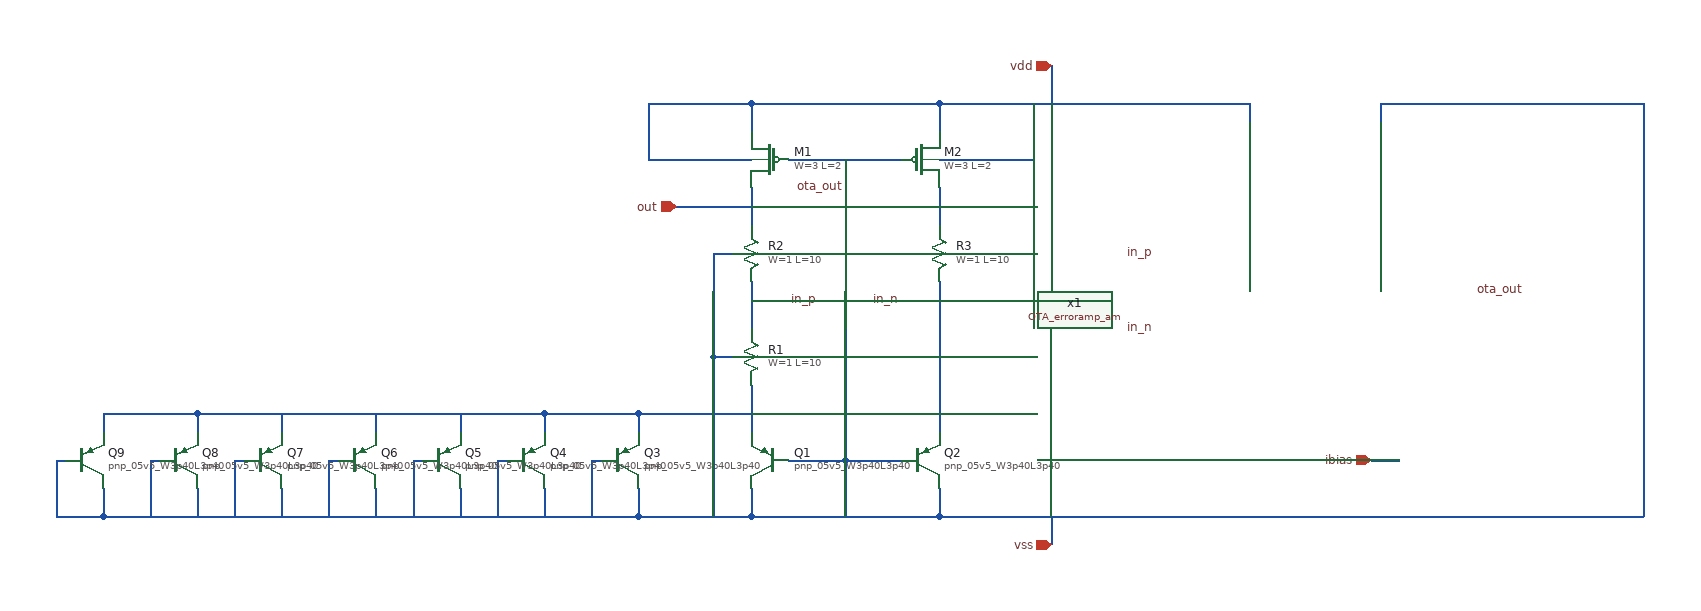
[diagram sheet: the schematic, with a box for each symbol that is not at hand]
v {xschem version=3.4.2 file_version=1.2
}
G {}
K {}
V {}
S {}
E {}
N 760 -70 760 -40 {
lab=vss}
N 960 -70 960 -40 {
lab=vss}
N 760 -180 760 -130 {
lab=#net1}
N 640 -150 640 -130 {
lab=#net1}
N 640 -150 760 -150 {
lab=#net1}
N 640 -70 640 -40 {
lab=vss}
N 640 -40 760 -40 {
lab=vss}
N 540 -150 540 -130 {
lab=#net1}
N 540 -150 640 -150 {
lab=#net1}
N 170 -150 170 -130 {
lab=#net1}
N 170 -150 540 -150 {
lab=#net1}
N 450 -150 450 -130 {
lab=#net1}
N 360 -150 360 -130 {
lab=#net1}
N 260 -150 260 -130 {
lab=#net1}
N 70 -150 70 -130 {
lab=#net1}
N 70 -150 170 -150 {
lab=#net1}
N 70 -70 70 -40 {
lab=vss}
N 70 -40 640 -40 {
lab=vss}
N 540 -70 540 -40 {
lab=vss}
N 450 -70 450 -40 {
lab=vss}
N 360 -70 360 -40 {
lab=vss}
N 260 -70 260 -40 {
lab=vss}
N 170 -70 170 -40 {
lab=vss}
N 590 -100 600 -100 {
lab=vss}
N 590 -100 590 -40 {
lab=vss}
N 490 -100 500 -100 {
lab=vss}
N 490 -100 490 -40 {
lab=vss}
N 400 -100 410 -100 {
lab=vss}
N 400 -100 400 -40 {
lab=vss}
N 310 -100 320 -100 {
lab=vss}
N 310 -100 310 -40 {
lab=vss}
N 210 -100 220 -100 {
lab=vss}
N 210 -100 210 -40 {
lab=vss}
N 120 -100 130 -100 {
lab=vss}
N 120 -100 120 -40 {
lab=vss}
N 20 -100 30 -100 {
lab=vss}
N 20 -100 20 -40 {
lab=vss}
N 20 -40 70 -40 {
lab=vss}
N 760 -290 760 -240 {
lab=in_p}
N 960 -290 960 -130 {
lab=in_n}
N 760 -40 960 -40 {
lab=vss}
N 760 -390 760 -350 {
lab=out}
N 960 -390 960 -360 {
lab=#net2}
N 960 -360 960 -350 {
lab=#net2}
N 800 -420 920 -420 {
lab=ota_out}
N 760 -480 760 -450 {
lab=vdd}
N 760 -480 960 -480 {
lab=vdd}
N 960 -480 960 -450 {
lab=vdd}
N 760 -270 800 -270 {
lab=in_p}
N 920 -270 960 -270 {
lab=in_n}
N 860 -420 860 -390 {
lab=ota_out}
N 960 -480 1290 -480 {
lab=vdd}
N 1290 -480 1290 -460 {
lab=vdd}
N 1430 -480 1430 -460 {
lab=vss}
N 1430 -480 1710 -480 {
lab=vss}
N 1710 -480 1710 -40 {
lab=vss}
N 960 -40 1710 -40 {
lab=vss}
N 1420 -100 1450 -100 {
lab=ibias}
N 1080 -520 1080 -480 {
lab=vdd}
N 1080 -40 1080 -10 {
lab=vss}
N 680 -370 760 -370 {
lab=out}
N 720 -320 740 -320 {
lab=vss}
N 720 -320 720 -210 {
lab=vss}
N 720 -210 740 -210 {
lab=vss}
N 720 -210 720 -40 {
lab=vss}
N 930 -320 940 -320 {
lab=vss}
N 860 -320 930 -320 {
lab=vss}
N 860 -320 860 -100 {
lab=vss}
N 800 -100 860 -100 {
lab=vss}
N 860 -100 920 -100 {
lab=vss}
N 860 -100 860 -40 {
lab=vss}
N 650 -420 760 -420 {
lab=vdd}
N 650 -480 650 -420 {
lab=vdd}
N 650 -480 760 -480 {
lab=vdd}
N 960 -420 1060 -420 {
lab=vdd}
N 1060 -480 1060 -420 {
lab=vdd}
C {sky130_fd_pr/pnp_05v5.sym} 780 -100 0 1 {name=Q1
model=pnp_05v5_W3p40L3p40
m=1
spiceprefix=X
}
C {sky130_fd_pr/pnp_05v5.sym} 940 -100 0 0 {name=Q2
model=pnp_05v5_W3p40L3p40
m=1
spiceprefix=X
}
C {sky130_fd_pr/pnp_05v5.sym} 620 -100 0 0 {name=Q3
model=pnp_05v5_W3p40L3p40
m=1
spiceprefix=X
}
C {sky130_fd_pr/pnp_05v5.sym} 520 -100 0 0 {name=Q4
model=pnp_05v5_W3p40L3p40
m=1
spiceprefix=X
}
C {sky130_fd_pr/pnp_05v5.sym} 430 -100 0 0 {name=Q5
model=pnp_05v5_W3p40L3p40
m=1
spiceprefix=X
}
C {sky130_fd_pr/pnp_05v5.sym} 340 -100 0 0 {name=Q6
model=pnp_05v5_W3p40L3p40
m=1
spiceprefix=X
}
C {sky130_fd_pr/pnp_05v5.sym} 240 -100 0 0 {name=Q7
model=pnp_05v5_W3p40L3p40
m=1
spiceprefix=X
}
C {sky130_fd_pr/pnp_05v5.sym} 150 -100 0 0 {name=Q8
model=pnp_05v5_W3p40L3p40
m=1
spiceprefix=X
}
C {sky130_fd_pr/pnp_05v5.sym} 50 -100 0 0 {name=Q9
model=pnp_05v5_W3p40L3p40
m=1
spiceprefix=X
}
C {sky130_fd_pr/res_xhigh_po.sym} 760 -210 0 0 {name=R1
W=1
L=10
model=res_xhigh_po
spiceprefix=X
mult=9}
C {sky130_fd_pr/res_xhigh_po.sym} 760 -320 0 0 {name=R2
W=1
L=10
model=res_xhigh_po
spiceprefix=X
mult=1}
C {sky130_fd_pr/res_xhigh_po.sym} 960 -320 0 0 {name=R3
W=1
L=10
model=res_xhigh_po
spiceprefix=X
mult=1}
C {devices/lab_pin.sym} 860 -390 0 0 {name=p1 sig_type=std_logic lab=ota_out}
C {devices/lab_pin.sym} 800 -270 2 0 {name=p2 sig_type=std_logic lab=in_p}
C {devices/lab_pin.sym} 920 -270 0 0 {name=p3 sig_type=std_logic lab=in_n}
C {devices/lab_pin.sym} 1190 -320 0 0 {name=p4 sig_type=std_logic lab=in_p}
C {devices/lab_pin.sym} 1190 -240 0 0 {name=p5 sig_type=std_logic lab=in_n}
C {devices/iopin.sym} 1080 -520 0 0 {name=p6 lab=vdd}
C {devices/iopin.sym} 1080 -10 0 0 {name=p7 lab=vss}
C {devices/lab_pin.sym} 1530 -280 2 0 {name=p8 sig_type=std_logic lab=ota_out}
C {devices/iopin.sym} 680 -370 2 0 {name=p9 lab=out}
C {devices/iopin.sym} 1420 -100 2 0 {name=p10 lab=ibias}
C {sky130_fd_pr/pfet_g5v0d10v5.sym} 780 -420 0 1 {name=M1
L=2
W=3
nf=1
mult=8
ad="'int((nf+1)/2) * W/nf * 0.29'" 
pd="'2*int((nf+1)/2) * (W/nf + 0.29)'"
as="'int((nf+2)/2) * W/nf * 0.29'" 
ps="'2*int((nf+2)/2) * (W/nf + 0.29)'"
nrd="'0.29 / W'" nrs="'0.29 / W'"
sa=0 sb=0 sd=0
model=pfet_g5v0d10v5
spiceprefix=X
}
C {sky130_fd_pr/pfet_g5v0d10v5.sym} 940 -420 0 0 {name=M2
L=2
W=3
nf=1
mult=8
ad="'int((nf+1)/2) * W/nf * 0.29'" 
pd="'2*int((nf+1)/2) * (W/nf + 0.29)'"
as="'int((nf+2)/2) * W/nf * 0.29'" 
ps="'2*int((nf+2)/2) * (W/nf + 0.29)'"
nrd="'0.29 / W'" nrs="'0.29 / W'"
sa=0 sb=0 sd=0
model=pfet_g5v0d10v5
spiceprefix=X
}
C {/foss/designs/Open3LFCC_V2/OTA_erroramp_am.sym} 1350 -280 0 0 {name=x1}
